VERSION 5.8 ;
BUSBITCHARS "[]" ;
DIVIDERCHAR "/" ;
UNITS
    DATABASE MICRONS 1000 ;
END UNITS

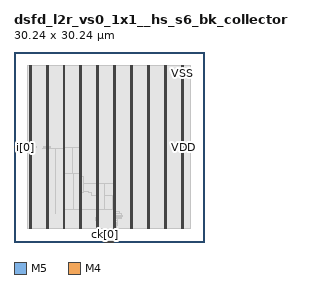
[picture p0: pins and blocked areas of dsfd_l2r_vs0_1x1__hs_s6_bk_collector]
MACRO dsfd_l2r_vs0_1x1__hs_s6_bk_collector
  FOREIGN dsfd_l2r_vs0_1x1__hs_s6_bk_collector 0 0 ;
  CLASS BLOCK ;
  SIZE 30.24 BY 30.24 ;
  PIN ck[0]
    DIRECTION INPUT ;
    USE SIGNAL ;
    PORT
      LAYER M5 ;
        RECT  14.4 0 14.424 0.084 ;
    END
  END ck[0]
  PIN cks[0]
    DIRECTION INPUT ;
    USE SIGNAL ;
    PORT
      LAYER M5 ;
        RECT  14.592 0 14.616 0.084 ;
    END
  END cks[0]
  PIN fo[0]
    DIRECTION OUTPUT ;
    USE SIGNAL ;
    PORT
      LAYER M5 ;
        RECT  14.784 0 14.808 0.084 ;
    END
  END fo[0]
  PIN i[0]
    DIRECTION INPUT ;
    USE SIGNAL ;
    PORT
      LAYER M4 ;
        RECT  0 15.072 0.084 15.096 ;
    END
  END i[0]
  PIN i[1]
    DIRECTION INPUT ;
    USE SIGNAL ;
    PORT
      LAYER M4 ;
        RECT  0 15.12 0.084 15.144 ;
    END
  END i[1]
  PIN od[0]
    DIRECTION OUTPUT ;
    USE SIGNAL ;
    PORT
      LAYER M5 ;
        RECT  14.976 0 15 0.084 ;
    END
  END od[0]
  PIN od[1]
    DIRECTION OUTPUT ;
    USE SIGNAL ;
    PORT
      LAYER M5 ;
        RECT  15.024 0 15.048 0.084 ;
    END
  END od[1]
  PIN od[2]
    DIRECTION OUTPUT ;
    USE SIGNAL ;
    PORT
      LAYER M5 ;
        RECT  15.072 0 15.096 0.084 ;
    END
  END od[2]
  PIN rs[0]
    DIRECTION INPUT ;
    USE SIGNAL ;
    PORT
      LAYER M5 ;
        RECT  15.264 0 15.288 0.084 ;
    END
  END rs[0]
  PIN rss[0]
    DIRECTION INPUT ;
    USE SIGNAL ;
    PORT
      LAYER M5 ;
        RECT  15.456 0 15.48 0.084 ;
    END
  END rss[0]
  PIN xf[0]
    DIRECTION INPUT ;
    USE SIGNAL ;
    PORT
      LAYER M5 ;
        RECT  15.648 0 15.672 0.084 ;
    END
  END xf[0]
  PIN xf[1]
    DIRECTION INPUT ;
    USE SIGNAL ;
    PORT
      LAYER M5 ;
        RECT  15.696 0 15.72 0.084 ;
    END
  END xf[1]
  PIN xf[2]
    DIRECTION INPUT ;
    USE SIGNAL ;
    PORT
      LAYER M5 ;
        RECT  15.744 0 15.768 0.084 ;
    END
  END xf[2]
  PIN xf[3]
    DIRECTION INPUT ;
    USE SIGNAL ;
    PORT
      LAYER M5 ;
        RECT  15.792 0 15.816 0.084 ;
    END
  END xf[3]
  PIN VDD
    DIRECTION INOUT ;
    USE POWER ;
    PORT
      LAYER M5 ;
        RECT  26.892 2.151 27.012 28.089 ;
        RECT  24.192 2.151 24.312 28.089 ;
        RECT  21.492 2.151 21.612 28.089 ;
        RECT  18.792 2.151 18.912 28.089 ;
        RECT  16.092 2.151 16.212 28.089 ;
        RECT  13.392 2.151 13.512 28.089 ;
        RECT  10.692 2.151 10.812 28.089 ;
        RECT  7.992 2.151 8.112 28.089 ;
        RECT  5.292 2.151 5.412 28.089 ;
        RECT  2.592 2.151 2.712 28.089 ;
    END
  END VDD
  PIN VSS
    DIRECTION INOUT ;
    USE GROUND ;
    PORT
      LAYER M5 ;
        RECT  26.7 2.137 26.82 28.103 ;
        RECT  24 2.137 24.12 28.103 ;
        RECT  21.3 2.137 21.42 28.103 ;
        RECT  18.6 2.137 18.72 28.103 ;
        RECT  15.9 2.137 16.02 28.103 ;
        RECT  13.2 2.137 13.32 28.103 ;
        RECT  10.5 2.137 10.62 28.103 ;
        RECT  7.8 2.137 7.92 28.103 ;
        RECT  5.1 2.137 5.22 28.103 ;
        RECT  2.4 2.137 2.52 28.103 ;
    END
  END VSS
  # OT_OBS_CLOSED layer=M5 d_um=1.536 added=8
  OBS
    LAYER RVTN ;
     RECT  2.16 2.16 28.08 2.295 ;
     RECT  2.16 2.565 28.08 2.835 ;
     RECT  2.16 3.105 28.08 3.375 ;
     RECT  2.16 3.645 28.08 3.915 ;
     RECT  2.16 4.185 28.08 4.455 ;
     RECT  2.16 4.725 28.08 4.995 ;
     RECT  2.16 5.265 28.08 5.535 ;
     RECT  2.16 5.805 28.08 6.075 ;
     RECT  2.16 6.345 28.08 6.615 ;
     RECT  2.16 6.885 28.08 7.155 ;
     RECT  2.16 7.425 28.08 7.695 ;
     RECT  2.16 7.965 28.08 8.235 ;
     RECT  2.16 8.505 28.08 8.775 ;
     RECT  2.16 9.045 28.08 9.315 ;
     RECT  2.16 9.585 28.08 9.855 ;
     RECT  2.16 10.125 28.08 10.395 ;
     RECT  2.16 10.665 28.08 10.935 ;
     RECT  2.16 11.205 28.08 11.475 ;
     RECT  2.16 11.745 28.08 12.015 ;
     RECT  2.16 12.285 28.08 12.555 ;
     RECT  2.16 12.825 28.08 13.095 ;
     RECT  2.16 13.365 28.08 13.635 ;
     RECT  2.16 13.905 28.08 14.175 ;
     RECT  2.16 14.445 28.08 14.715 ;
     RECT  2.16 14.985 28.08 15.255 ;
     RECT  2.16 15.525 28.08 15.795 ;
     RECT  2.16 16.065 28.08 16.335 ;
     RECT  2.16 16.605 28.08 16.875 ;
     RECT  2.16 17.145 28.08 17.415 ;
     RECT  2.16 17.685 28.08 17.955 ;
     RECT  2.16 18.225 28.08 18.495 ;
     RECT  2.16 18.765 28.08 19.035 ;
     RECT  2.16 19.305 28.08 19.575 ;
     RECT  2.16 19.845 28.08 20.115 ;
     RECT  2.16 20.385 28.08 20.655 ;
     RECT  2.16 20.925 28.08 21.195 ;
     RECT  2.16 21.465 28.08 21.735 ;
     RECT  2.16 22.005 28.08 22.275 ;
     RECT  2.16 22.545 28.08 22.815 ;
     RECT  2.16 23.085 28.08 23.355 ;
     RECT  2.16 23.625 28.08 23.895 ;
     RECT  2.16 24.165 28.08 24.435 ;
     RECT  2.16 24.705 28.08 24.975 ;
     RECT  2.16 25.245 28.08 25.515 ;
     RECT  2.16 25.785 28.08 26.055 ;
     RECT  2.16 26.325 28.08 26.595 ;
     RECT  2.16 26.865 28.08 27.135 ;
     RECT  2.16 27.405 28.08 27.675 ;
     RECT  2.16 27.945 28.08 28.08 ;
    LAYER RVTP ;
     RECT  2.16 2.295 28.08 2.565 ;
     RECT  2.16 2.835 28.08 3.105 ;
     RECT  2.16 3.375 28.08 3.645 ;
     RECT  2.16 3.915 28.08 4.185 ;
     RECT  2.16 4.455 28.08 4.725 ;
     RECT  2.16 4.995 28.08 5.265 ;
     RECT  2.16 5.535 28.08 5.805 ;
     RECT  2.16 6.075 28.08 6.345 ;
     RECT  2.16 6.615 28.08 6.885 ;
     RECT  2.16 7.155 28.08 7.425 ;
     RECT  2.16 7.695 28.08 7.965 ;
     RECT  2.16 8.235 28.08 8.505 ;
     RECT  2.16 8.775 28.08 9.045 ;
     RECT  2.16 9.315 28.08 9.585 ;
     RECT  2.16 9.855 28.08 10.125 ;
     RECT  2.16 10.395 28.08 10.665 ;
     RECT  2.16 10.935 28.08 11.205 ;
     RECT  2.16 11.475 28.08 11.745 ;
     RECT  2.16 12.015 28.08 12.285 ;
     RECT  2.16 12.555 28.08 12.825 ;
     RECT  2.16 13.095 28.08 13.365 ;
     RECT  2.16 13.635 28.08 13.905 ;
     RECT  2.16 14.175 28.08 14.445 ;
     RECT  2.16 14.715 28.08 14.985 ;
     RECT  2.16 15.255 28.08 15.525 ;
     RECT  2.16 15.795 28.08 16.065 ;
     RECT  2.16 16.335 28.08 16.605 ;
     RECT  2.16 16.875 28.08 17.145 ;
     RECT  2.16 17.415 28.08 17.685 ;
     RECT  2.16 17.955 28.08 18.225 ;
     RECT  2.16 18.495 28.08 18.765 ;
     RECT  2.16 19.035 28.08 19.305 ;
     RECT  2.16 19.575 28.08 19.845 ;
     RECT  2.16 20.115 28.08 20.385 ;
     RECT  2.16 20.655 28.08 20.925 ;
     RECT  2.16 21.195 28.08 21.465 ;
     RECT  2.16 21.735 28.08 22.005 ;
     RECT  2.16 22.275 28.08 22.545 ;
     RECT  2.16 22.815 28.08 23.085 ;
     RECT  2.16 23.355 28.08 23.625 ;
     RECT  2.16 23.895 28.08 24.165 ;
     RECT  2.16 24.435 28.08 24.705 ;
     RECT  2.16 24.975 28.08 25.245 ;
     RECT  2.16 25.515 28.08 25.785 ;
     RECT  2.16 26.055 28.08 26.325 ;
     RECT  2.16 26.595 28.08 26.865 ;
     RECT  2.16 27.135 28.08 27.405 ;
     RECT  2.16 27.675 28.08 27.945 ;
    LAYER M1 ;
     RECT  2.16 2.151 28.08 28.089 ;
    LAYER M2 ;
     RECT  2.16 2.151 28.08 28.089 ;
    LAYER M3 ;
     RECT  15.156 0.139 15.174 0.235 ;
     RECT  15.048 0.235 15.174 0.523 ;
     RECT  14.94 0.523 15.462 1.723 ;
     RECT  14.94 1.723 15.786 1.819 ;
     RECT  14.94 1.819 15.822 2.143 ;
     RECT  14.94 2.143 16.005 2.191 ;
     RECT  14.94 2.191 16.29 2.299 ;
     RECT  13.215 2.143 13.305 2.371 ;
     RECT  14.544 2.299 16.29 2.371 ;
     RECT  2.415 2.143 2.505 2.413 ;
     RECT  5.115 2.143 5.205 2.413 ;
     RECT  7.815 2.143 7.905 2.413 ;
     RECT  10.515 2.143 10.605 2.413 ;
     RECT  18.615 2.143 18.705 2.413 ;
     RECT  21.315 2.143 21.405 2.413 ;
     RECT  24.015 2.143 24.105 2.413 ;
     RECT  26.715 2.143 26.805 2.413 ;
     RECT  13.215 2.371 16.326 2.641 ;
     RECT  13.215 2.641 16.398 2.839 ;
     RECT  13.215 2.839 16.47 2.911 ;
     RECT  13.215 2.911 16.506 3.181 ;
     RECT  13.215 3.181 16.542 3.343 ;
     RECT  13.14 3.343 16.542 3.451 ;
     RECT  13.032 3.451 16.542 3.721 ;
     RECT  13.032 3.721 17.082 3.911 ;
     RECT  13.215 3.911 17.082 3.991 ;
     RECT  5.115 2.413 5.397 4.189 ;
     RECT  13.215 3.991 17.19 4.253 ;
     RECT  13.215 4.253 17.082 4.523 ;
     RECT  13.215 4.523 16.722 4.919 ;
     RECT  13.215 4.919 16.197 5.189 ;
     RECT  13.215 5.189 14.022 5.225 ;
     RECT  14.796 5.189 16.197 5.225 ;
     RECT  14.976 5.225 16.197 5.261 ;
     RECT  15.048 5.261 16.197 5.459 ;
     RECT  15.3 5.459 16.197 5.495 ;
     RECT  15.372 5.495 16.197 5.729 ;
     RECT  15.444 5.729 16.197 5.873 ;
     RECT  12.384 7.435 12.402 7.861 ;
     RECT  11.808 7.861 12.402 7.889 ;
     RECT  11.808 7.889 11.826 7.997 ;
     RECT  10.515 2.413 10.797 9.115 ;
     RECT  10.515 9.115 10.854 9.163 ;
     RECT  10.515 9.163 10.998 9.275 ;
     RECT  10.515 9.275 10.854 9.293 ;
     RECT  9.252 10.315 9.27 10.741 ;
     RECT  9.252 10.741 9.522 11.003 ;
     RECT  9.252 11.003 9.27 11.021 ;
     RECT  5.115 4.189 5.49 14.881 ;
     RECT  6.552 4.459 6.57 14.909 ;
     RECT  4.536 14.881 5.634 14.957 ;
     RECT  2.415 2.413 2.697 15.025 ;
     RECT  4.68 14.957 5.634 15.061 ;
     RECT  2.304 15.025 2.697 15.115 ;
     RECT  3.6 15.061 3.618 15.179 ;
     RECT  4.68 15.061 5.778 15.179 ;
     RECT  2.232 15.115 2.697 15.215 ;
     RECT  5.115 15.179 5.778 15.251 ;
     RECT  2.415 15.215 2.697 27.827 ;
     RECT  5.115 15.251 5.397 27.827 ;
     RECT  7.815 2.413 8.097 27.827 ;
     RECT  10.515 9.293 10.797 27.827 ;
     RECT  13.215 5.225 13.497 27.827 ;
     RECT  15.915 5.873 16.197 27.827 ;
     RECT  18.615 2.413 18.897 27.827 ;
     RECT  21.315 2.413 21.597 27.827 ;
     RECT  24.015 2.413 24.297 27.827 ;
     RECT  26.715 2.413 26.997 27.827 ;
     RECT  2.415 27.827 2.505 28.097 ;
     RECT  5.115 27.827 5.205 28.097 ;
     RECT  7.815 27.827 7.905 28.097 ;
     RECT  10.515 27.827 10.605 28.097 ;
     RECT  13.215 27.827 13.305 28.097 ;
     RECT  15.915 27.827 16.005 28.097 ;
     RECT  18.615 27.827 18.705 28.097 ;
     RECT  21.315 27.827 21.405 28.097 ;
     RECT  24.015 27.827 24.105 28.097 ;
     RECT  26.715 27.827 26.805 28.097 ;
    LAYER M4 ;
     RECT  0.06 15.072 2.408 15.144 ;
     RECT  2.408 2.148 2.512 28.092 ;
     RECT  2.512 2.418 2.704 27.822 ;
     RECT  4.525 14.928 5.108 14.952 ;
     RECT  5.108 2.148 5.212 28.092 ;
     RECT  5.212 2.418 5.404 27.822 ;
     RECT  5.404 14.928 7.808 14.952 ;
     RECT  7.808 2.148 7.912 28.092 ;
     RECT  7.912 2.418 8.104 27.822 ;
     RECT  9.212 10.992 9.241 11.016 ;
     RECT  9.241 10.32 9.299 11.016 ;
     RECT  8.104 14.928 9.299 14.952 ;
     RECT  9.299 10.32 9.539 10.824 ;
     RECT  9.493 5.184 10.508 5.208 ;
     RECT  9.539 10.32 10.508 10.344 ;
     RECT  10.508 2.148 10.612 28.092 ;
     RECT  10.612 2.418 10.804 27.822 ;
     RECT  10.804 9.12 10.865 9.288 ;
     RECT  10.804 10.32 11.027 10.344 ;
     RECT  10.865 9.168 11.053 9.288 ;
     RECT  10.804 7.968 11.837 7.992 ;
     RECT  13.129 3.36 13.208 3.384 ;
     RECT  10.804 5.184 13.208 5.208 ;
     RECT  12.373 7.44 13.208 7.464 ;
     RECT  11.053 9.264 13.208 9.288 ;
     RECT  13.208 2.148 13.312 28.092 ;
     RECT  13.312 2.418 13.504 27.822 ;
     RECT  13.504 5.088 14.033 5.208 ;
     RECT  13.504 9.264 14.435 9.288 ;
     RECT  13.504 3.36 14.485 4.008 ;
     RECT  14.033 5.088 14.485 5.16 ;
     RECT  14.485 3.36 14.531 5.16 ;
     RECT  14.533 2.304 14.819 2.328 ;
     RECT  14.924 0.528 15.013 0.552 ;
     RECT  15.013 0.144 15.185 0.552 ;
     RECT  15.185 0.528 15.491 0.552 ;
     RECT  14.531 3.696 15.685 5.16 ;
     RECT  15.397 1.728 15.82 1.848 ;
     RECT  15.82 1.824 15.868 1.848 ;
     RECT  15.685 3.168 15.908 5.16 ;
     RECT  13.504 7.44 15.908 7.464 ;
     RECT  15.908 2.148 16.012 28.092 ;
     RECT  16.012 2.418 16.204 27.822 ;
     RECT  16.204 3.936 16.265 3.96 ;
     RECT  18.608 2.148 18.712 28.092 ;
     RECT  18.712 2.418 18.904 27.822 ;
     RECT  21.308 2.148 21.412 28.092 ;
     RECT  21.412 2.418 21.604 27.822 ;
     RECT  24.008 2.148 24.112 28.092 ;
     RECT  24.112 2.418 24.304 27.822 ;
     RECT  26.708 2.148 26.812 28.092 ;
     RECT  26.812 2.418 27.004 27.822 ;
    LAYER M5 ;
     RECT  14.4 0.016 15.816 2.137 ;
     RECT  2.4 2.137 2.52 2.151 ;
     RECT  5.1 2.137 5.22 2.151 ;
     RECT  7.8 2.137 7.92 2.151 ;
     RECT  10.5 2.137 10.62 2.151 ;
     RECT  13.2 2.137 13.32 2.151 ;
     RECT  14.4 2.137 16.02 2.151 ;
     RECT  18.6 2.137 18.72 2.151 ;
     RECT  21.3 2.137 21.42 2.151 ;
     RECT  24 2.137 24.12 2.151 ;
     RECT  26.7 2.137 26.82 2.151 ;
     RECT  13.2 2.151 16.212 5.171 ;
     RECT  15.696 5.171 16.212 7.475 ;
     RECT  10.5 2.151 10.812 7.957 ;
     RECT  13.2 5.171 14.424 9.299 ;
     RECT  10.5 7.957 11.016 10.355 ;
     RECT  9.504 5.173 9.528 10.835 ;
     RECT  9.264 10.981 9.288 14.963 ;
     RECT  2.4 2.151 2.712 28.089 ;
     RECT  5.1 2.151 5.412 28.089 ;
     RECT  7.8 2.151 8.112 28.089 ;
     RECT  10.5 10.355 10.812 28.089 ;
     RECT  13.2 9.299 13.512 28.089 ;
     RECT  15.9 7.475 16.212 28.089 ;
     RECT  18.6 2.151 18.912 28.089 ;
     RECT  21.3 2.151 21.612 28.089 ;
     RECT  24 2.151 24.312 28.089 ;
     RECT  26.7 2.151 27.012 28.089 ;
     RECT  2.4 28.089 2.52 28.103 ;
     RECT  5.1 28.089 5.22 28.103 ;
     RECT  7.8 28.089 7.92 28.103 ;
     RECT  10.5 28.089 10.62 28.103 ;
     RECT  13.2 28.089 13.32 28.103 ;
     RECT  15.9 28.089 16.02 28.103 ;
     RECT  18.6 28.089 18.72 28.103 ;
     RECT  21.3 28.089 21.42 28.103 ;
     RECT  24 28.089 24.12 28.103 ;
     RECT  26.7 28.089 26.82 28.103 ;
     RECT  13.32 2.137 14.4 2.151 ;
     RECT  14.424 5.171 15.696 7.475 ;
     RECT  8.112 5.173 9.504 10.835 ;
     RECT  9.528 5.173 10.5 10.835 ;
     RECT  14.424 7.475 15.9 9.299 ;
     RECT  8.112 10.835 10.5 10.981 ;
     RECT  8.112 10.981 9.264 14.963 ;
     RECT  9.288 10.981 10.5 14.963 ;
  END
END dsfd_l2r_vs0_1x1__hs_s6_bk_collector
END LIBRARY
